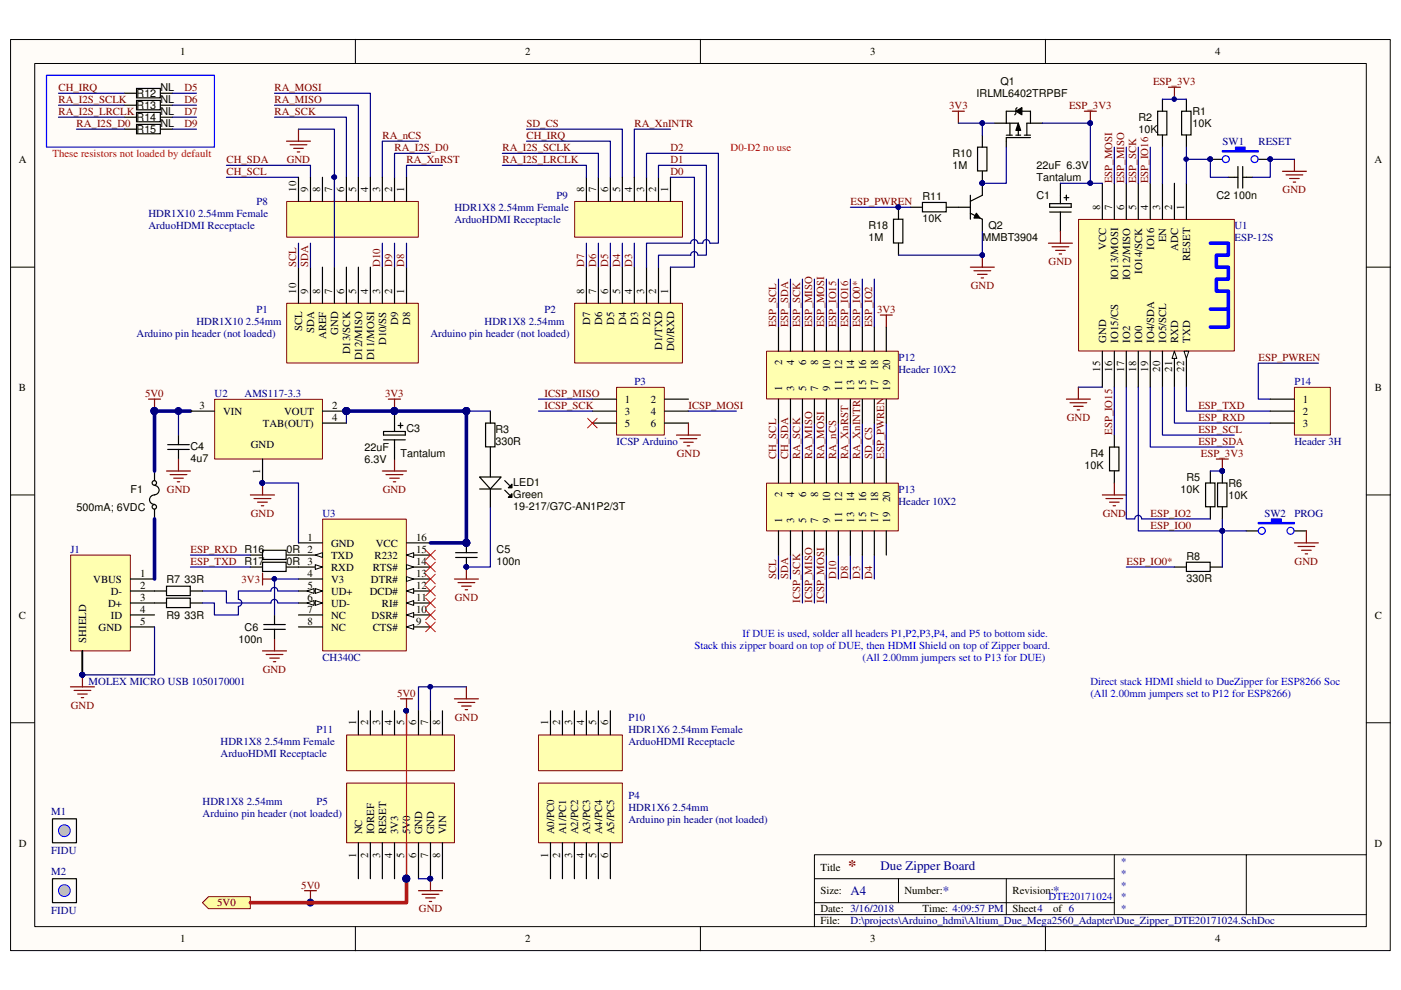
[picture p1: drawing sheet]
<svg xmlns="http://www.w3.org/2000/svg" width="297mm" height="210mm" viewBox="0 0 297 210" stroke-linecap="round" stroke-linejoin="round" font-family="sans-serif">
<defs><g id="words">
<text font-size="3.4" fill="#800000" x="179.8" y="184.6">*</text>
<g font-size="2.8" fill="#000080">
<text x="186.7" y="184.5">Due Zipper Board</text>
<text x="180.3" y="189.8">A4</text>
<text x="199.9" y="189.8">*</text>
<text x="223.3" y="189.8">*</text>
</g>
<g font-size="2.3">
<text x="38.2" y="11.7">1</text>
<text x="111.4" y="11.7">2</text>
<text x="184.5" y="11.7">3</text>
<text x="257.6" y="11.7">4</text>
<text x="29" y="20.6">R12</text>
<text x="29" y="23.1">R13</text>
<text x="34" y="21.8">NL</text>
<text x="34" y="19.3">NL</text>
<text x="207" y="20.6">IRLML6402TRPBF</text>
<text x="212.1" y="18">Q1</text>
<text x="29" y="28.2">R15</text>
<text x="29" y="25.7">R14</text>
<text x="34" y="26.9">NL</text>
<text x="34" y="24.4">NL</text>
<text x="241.4" y="25.7">R2</text>
<text x="241.4" y="28.2">10K</text>
<text x="252.8" y="26.9">10K</text>
<text x="252.8" y="24.4">R1</text>
<text x="4" y="34.5">A</text>
<text x="201.9" y="35.9">1M</text>
<text x="201.9" y="33.3">R10</text>
<text x="219.7" y="35.9">22uF 6.3V</text>
<text x="291.4" y="34.5">A</text>
<text x="62.8" y="40.6" transform="rotate(-90 62.8 40.6)">10</text>
<text x="65.4" y="40.6" transform="rotate(-90 65.4 40.6)">9</text>
<text x="67.9" y="40.6" transform="rotate(-90 67.9 40.6)">8</text>
<text x="70.4" y="40.6" transform="rotate(-90 70.4 40.6)">7</text>
<text x="73" y="40.6" transform="rotate(-90 73 40.6)">6</text>
<text x="75.5" y="40.6" transform="rotate(-90 75.5 40.6)">5</text>
<text x="78.1" y="40.6" transform="rotate(-90 78.1 40.6)">4</text>
<text x="80.6" y="40.6" transform="rotate(-90 80.6 40.6)">3</text>
<text x="83.1" y="40.6" transform="rotate(-90 83.1 40.6)">2</text>
<text x="85.7" y="40.6" transform="rotate(-90 85.7 40.6)">1</text>
<text x="123.9" y="40.6" transform="rotate(-90 123.9 40.6)">8</text>
<text x="126.4" y="40.6" transform="rotate(-90 126.4 40.6)">7</text>
<text x="128.9" y="40.6" transform="rotate(-90 128.9 40.6)">6</text>
<text x="131.5" y="40.6" transform="rotate(-90 131.5 40.6)">5</text>
<text x="134" y="40.6" transform="rotate(-90 134 40.6)">4</text>
<text x="136.6" y="40.6" transform="rotate(-90 136.6 40.6)">3</text>
<text x="139.1" y="40.6" transform="rotate(-90 139.1 40.6)">2</text>
<text x="141.6" y="40.6" transform="rotate(-90 141.6 40.6)">1</text>
<text x="219.7" y="38.4">Tantalum</text>
<text x="195.6" y="47">10K</text>
<text x="195.6" y="42.5">R11</text>
<text x="219.7" y="42.2">C1</text>
<text x="233.3" y="44.4" transform="rotate(-90 233.3 44.4)">8</text>
<text x="235.8" y="44.4" transform="rotate(-90 235.8 44.4)">7</text>
<text x="238.3" y="44.4" transform="rotate(-90 238.3 44.4)">6</text>
<text x="240.9" y="44.4" transform="rotate(-90 240.9 44.4)">5</text>
<text x="243.4" y="44.4" transform="rotate(-90 243.4 44.4)">4</text>
<text x="246" y="44.4" transform="rotate(-90 246 44.4)">3</text>
<text x="248.5" y="44.4" transform="rotate(-90 248.5 44.4)">2</text>
<text x="251.1" y="44.4" transform="rotate(-90 251.1 44.4)">1</text>
<text x="257.9" y="42.2">C2</text>
<text x="261.5" y="42.2">100n</text>
<text x="184.1" y="51.1">1M</text>
<text x="184.1" y="48.6">R18</text>
<text x="208.3" y="51.1">MMBT3904</text>
<text x="209.6" y="48.6">Q2</text>
<text x="234.5" y="53" transform="rotate(-90 234.5 53)">VCC</text>
<text x="244.7" y="53" transform="rotate(-90 244.7 53)">IO16</text>
<text x="247.2" y="51.4" transform="rotate(-90 247.2 51.4)">EN</text>
<text x="249.8" y="53.1" transform="rotate(-90 249.8 53.1)">ADC</text>
<text x="237.1" y="59.4" transform="rotate(-90 237.1 59.4)">IO13/MOSI</text>
<text x="239.6" y="59.4" transform="rotate(-90 239.6 59.4)">IO12/MISO</text>
<text x="242.1" y="58.1" transform="rotate(-90 242.1 58.1)">IO14/SCK</text>
<text x="252.3" y="55.3" transform="rotate(-90 252.3 55.3)">RESET</text>
<text x="62.8" y="62.3" transform="rotate(-90 62.8 62.3)">10</text>
<text x="65.4" y="62.3" transform="rotate(-90 65.4 62.3)">9</text>
<text x="67.9" y="62.3" transform="rotate(-90 67.9 62.3)">8</text>
<text x="70.4" y="62.3" transform="rotate(-90 70.4 62.3)">7</text>
<text x="73" y="62.3" transform="rotate(-90 73 62.3)">6</text>
<text x="75.5" y="62.3" transform="rotate(-90 75.5 62.3)">5</text>
<text x="78.1" y="62.3" transform="rotate(-90 78.1 62.3)">4</text>
<text x="80.6" y="62.3" transform="rotate(-90 80.6 62.3)">3</text>
<text x="83.1" y="62.3" transform="rotate(-90 83.1 62.3)">2</text>
<text x="85.7" y="62.3" transform="rotate(-90 85.7 62.3)">1</text>
<text x="123.9" y="62.3" transform="rotate(-90 123.9 62.3)">8</text>
<text x="126.4" y="62.3" transform="rotate(-90 126.4 62.3)">7</text>
<text x="128.9" y="62.3" transform="rotate(-90 128.9 62.3)">6</text>
<text x="131.5" y="62.3" transform="rotate(-90 131.5 62.3)">5</text>
<text x="134" y="62.3" transform="rotate(-90 134 62.3)">4</text>
<text x="136.6" y="62.3" transform="rotate(-90 136.6 62.3)">3</text>
<text x="139.1" y="62.3" transform="rotate(-90 139.1 62.3)">2</text>
<text x="141.6" y="62.3" transform="rotate(-90 141.6 62.3)">1</text>
<text x="64.1" y="70.3" transform="rotate(-90 64.1 70.3)">SCL</text>
<text x="66.6" y="70.7" transform="rotate(-90 66.6 70.7)">SDA</text>
<text x="69.2" y="71.9" transform="rotate(-90 69.2 71.9)">AREF</text>
<text x="71.7" y="71" transform="rotate(-90 71.7 71)">GND</text>
<text x="84.4" y="68.9" transform="rotate(-90 84.4 68.9)">D9</text>
<text x="86.9" y="68.9" transform="rotate(-90 86.9 68.9)">D8</text>
<text x="125.1" y="68.9" transform="rotate(-90 125.1 68.9)">D7</text>
<text x="127.7" y="68.9" transform="rotate(-90 127.7 68.9)">D6</text>
<text x="130.2" y="68.9" transform="rotate(-90 130.2 68.9)">D5</text>
<text x="132.8" y="68.9" transform="rotate(-90 132.8 68.9)">D4</text>
<text x="135.3" y="68.9" transform="rotate(-90 135.3 68.9)">D3</text>
<text x="137.8" y="68.9" transform="rotate(-90 137.8 68.9)">D2</text>
<text x="74.2" y="75.1" transform="rotate(-90 74.2 75.1)">D13/SCK</text>
<text x="76.8" y="76.4" transform="rotate(-90 76.8 76.4)">D12/MISO</text>
<text x="79.3" y="76.4" transform="rotate(-90 79.3 76.4)">D11/MOSI</text>
<text x="81.9" y="73.2" transform="rotate(-90 81.9 73.2)">D10/SS</text>
<text x="140.4" y="74.3" transform="rotate(-90 140.4 74.3)">D1/TXD</text>
<text x="142.9" y="74.4" transform="rotate(-90 142.9 74.4)">D0/RXD</text>
<text x="165.8" y="77.4" transform="rotate(-90 165.8 77.4)">2</text>
<text x="168.4" y="77.4" transform="rotate(-90 168.4 77.4)">4</text>
<text x="170.9" y="77.4" transform="rotate(-90 170.9 77.4)">6</text>
<text x="173.5" y="77.4" transform="rotate(-90 173.5 77.4)">8</text>
<text x="234.5" y="72.7" transform="rotate(-90 234.5 72.7)">GND</text>
<text x="237.1" y="72.7" transform="rotate(-90 237.1 72.7)">IO15/CS</text>
<text x="239.6" y="72.7" transform="rotate(-90 239.6 72.7)">IO2</text>
<text x="242.1" y="72.7" transform="rotate(-90 242.1 72.7)">IO0</text>
<text x="244.7" y="72.7" transform="rotate(-90 244.7 72.7)">IO4/SDA</text>
<text x="247.2" y="72.7" transform="rotate(-90 247.2 72.7)">IO5/SCL</text>
<text x="249.8" y="72.7" transform="rotate(-90 249.8 72.7)">RXD</text>
<text x="252.3" y="72.7" transform="rotate(-90 252.3 72.7)">TXD</text>
<text x="4" y="82.8">B</text>
<text x="165.8" y="82.8" transform="rotate(-90 165.8 82.8)">1</text>
<text x="168.4" y="82.8" transform="rotate(-90 168.4 82.8)">3</text>
<text x="170.9" y="82.8" transform="rotate(-90 170.9 82.8)">5</text>
<text x="173.5" y="82.8" transform="rotate(-90 173.5 82.8)">7</text>
<text x="176" y="82.8" transform="rotate(-90 176 82.8)">9</text>
<text x="176" y="78.5" transform="rotate(-90 176 78.5)">10</text>
<text x="178.6" y="82.8" transform="rotate(-90 178.6 82.8)">11</text>
<text x="178.6" y="78.5" transform="rotate(-90 178.6 78.5)">12</text>
<text x="181.1" y="82.8" transform="rotate(-90 181.1 82.8)">13</text>
<text x="181.1" y="78.5" transform="rotate(-90 181.1 78.5)">14</text>
<text x="183.6" y="82.8" transform="rotate(-90 183.6 82.8)">15</text>
<text x="183.6" y="78.5" transform="rotate(-90 183.6 78.5)">16</text>
<text x="186.2" y="82.8" transform="rotate(-90 186.2 82.8)">17</text>
<text x="186.2" y="78.5" transform="rotate(-90 186.2 78.5)">18</text>
<text x="188.7" y="82.8" transform="rotate(-90 188.7 82.8)">19</text>
<text x="188.7" y="78.5" transform="rotate(-90 188.7 78.5)">20</text>
<text x="233.3" y="78.8" transform="rotate(-90 233.3 78.8)">15</text>
<text x="235.8" y="78.8" transform="rotate(-90 235.8 78.8)">16</text>
<text x="238.3" y="78.8" transform="rotate(-90 238.3 78.8)">17</text>
<text x="240.9" y="78.8" transform="rotate(-90 240.9 78.8)">18</text>
<text x="243.4" y="78.8" transform="rotate(-90 243.4 78.8)">19</text>
<text x="246" y="78.8" transform="rotate(-90 246 78.8)">20</text>
<text x="248.5" y="78.8" transform="rotate(-90 248.5 78.8)">21</text>
<text x="251.1" y="78.8" transform="rotate(-90 251.1 78.8)">22</text>
<text x="291.5" y="82.8">B</text>
<text x="42.3" y="86.7">3</text>
<text x="47.3" y="88">VIN</text>
<text x="60.2" y="88">VOUT</text>
<text x="70.4" y="86.7">2</text>
<text x="70.4" y="89.2">4</text>
<text x="132.5" y="85.4">1</text>
<text x="132.5" y="88">3</text>
<text x="138" y="85.4">2</text>
<text x="138" y="88">4</text>
<text x="276.2" y="85.4">1</text>
<text x="276.2" y="88">2</text>
<text x="40.4" y="95.3">C4</text>
<text x="53.2" y="95.1">GND</text>
<text x="55.7" y="90.5">TAB(OUT)</text>
<text x="77.3" y="95.6">22uF</text>
<text x="86.2" y="91.5">C3</text>
<text x="105" y="91.8">R3</text>
<text x="105" y="94.3">330R</text>
<text x="132.5" y="90.5">5</text>
<text x="138" y="90.5">6</text>
<text x="276.2" y="90.5">3</text>
<text x="40.4" y="97.9">4u7</text>
<text x="55.2" y="100.5" transform="rotate(-90 55.2 100.5)">1</text>
<text x="77.3" y="98.1">6.3V</text>
<text x="84.9" y="96.9">Tantalum</text>
<text x="229.9" y="99.4">10K</text>
<text x="231.2" y="96.9">R4</text>
<text x="251.5" y="101.9">R5</text>
<text x="27.7" y="104.5">F1</text>
<text x="108.8" y="103">LED1</text>
<text x="108.8" y="105.5">Green</text>
<text x="165.8" y="105.4" transform="rotate(-90 165.8 105.4)">2</text>
<text x="168.4" y="105.4" transform="rotate(-90 168.4 105.4)">4</text>
<text x="170.9" y="105.4" transform="rotate(-90 170.9 105.4)">6</text>
<text x="173.5" y="105.4" transform="rotate(-90 173.5 105.4)">8</text>
<text x="176" y="106.5" transform="rotate(-90 176 106.5)">10</text>
<text x="178.6" y="106.5" transform="rotate(-90 178.6 106.5)">12</text>
<text x="181.1" y="106.5" transform="rotate(-90 181.1 106.5)">14</text>
<text x="183.6" y="106.5" transform="rotate(-90 183.6 106.5)">16</text>
<text x="186.2" y="106.5" transform="rotate(-90 186.2 106.5)">18</text>
<text x="188.7" y="106.5" transform="rotate(-90 188.7 106.5)">20</text>
<text x="250.3" y="104.5">10K</text>
<text x="260.5" y="105.7">10K</text>
<text x="260.5" y="103.2">R6</text>
<text x="16.3" y="108.3">500mA; 6VDC</text>
<text x="108.8" y="108">19-217/G7C-AN1P2/3T</text>
<text x="165.8" y="110.8" transform="rotate(-90 165.8 110.8)">1</text>
<text x="168.4" y="110.8" transform="rotate(-90 168.4 110.8)">3</text>
<text x="170.9" y="110.8" transform="rotate(-90 170.9 110.8)">5</text>
<text x="173.5" y="110.8" transform="rotate(-90 173.5 110.8)">7</text>
<text x="176" y="110.8" transform="rotate(-90 176 110.8)">9</text>
<text x="178.6" y="110.8" transform="rotate(-90 178.6 110.8)">11</text>
<text x="181.1" y="110.8" transform="rotate(-90 181.1 110.8)">13</text>
<text x="183.6" y="110.8" transform="rotate(-90 183.6 110.8)">15</text>
<text x="186.2" y="110.8" transform="rotate(-90 186.2 110.8)">17</text>
<text x="188.7" y="110.8" transform="rotate(-90 188.7 110.8)">19</text>
<text x="51.9" y="119.8">R17</text>
<text x="60.7" y="117.2">0R 2</text>
<text x="60.7" y="119.8">0R 3</text>
<text x="65.2" y="114.6">1</text>
<text x="70.2" y="115.9">GND</text>
<text x="70.2" y="118.4">TXD</text>
<text x="79.4" y="118.4">R232</text>
<text x="79.7" y="115.9">VCC</text>
<text x="88.2" y="117.2">15</text>
<text x="88.2" y="119.7">14</text>
<text x="88.2" y="114.6">16</text>
<text x="105.3" y="119.8">100n</text>
<text x="105.3" y="117.2">C5</text>
<text x="251.5" y="118.7">R8</text>
<text x="19.8" y="123.5">VBUS</text>
<text x="29.7" y="122.3">1</text>
<text x="29.7" y="124.8">2</text>
<text x="35.3" y="123.6">R7</text>
<text x="39.1" y="123.6">33R</text>
<text x="65.2" y="122.3">4</text>
<text x="65.2" y="124.8">5</text>
<text x="70.2" y="121">RXD</text>
<text x="70.2" y="123.5">V3</text>
<text x="78.7" y="123.5">DTR#</text>
<text x="79" y="121">RTS#</text>
<text x="88.2" y="122.3">13</text>
<text x="88.2" y="124.8">12</text>
<text x="251.5" y="123.3">330R</text>
<text x="4" y="131.2">C</text>
<text x="22.9" y="128.7">D+</text>
<text x="23.5" y="126.1">D-</text>
<text x="23.5" y="131.2">ID</text>
<text x="29.7" y="127.4">3</text>
<text x="29.7" y="129.9">4</text>
<text x="35.3" y="131.2">R9</text>
<text x="39.1" y="131.2">33R</text>
<text x="65.2" y="127.4">6</text>
<text x="65.2" y="129.9">7</text>
<text x="70.2" y="126.1">UD+</text>
<text x="70.2" y="128.7">UD-</text>
<text x="70.2" y="131.2">NC</text>
<text x="78.4" y="126.1">DCD#</text>
<text x="78.8" y="131.2">DSR#</text>
<text x="81" y="128.7">RI#</text>
<text x="88.2" y="127.4">11</text>
<text x="88.2" y="129.9">10</text>
<text x="291.5" y="131.2">C</text>
<text x="18.3" y="136.2" transform="rotate(-90 18.3 136.2)">SHIELD</text>
<text x="20.9" y="133.7">GND</text>
<text x="29.7" y="132.5">5</text>
<text x="50.6" y="136.3">100n</text>
<text x="51.9" y="133.7">C6</text>
<text x="65.2" y="132.5">8</text>
<text x="70.2" y="133.7">NC</text>
<text x="79" y="133.7">CTS#</text>
<text x="88.2" y="132.5">9</text>
<text x="75.5" y="153.8" transform="rotate(-90 75.5 153.8)">1</text>
<text x="78.1" y="153.8" transform="rotate(-90 78.1 153.8)">2</text>
<text x="80.6" y="153.8" transform="rotate(-90 80.6 153.8)">3</text>
<text x="83.1" y="153.8" transform="rotate(-90 83.1 153.8)">4</text>
<text x="85.7" y="153.8" transform="rotate(-90 85.7 153.8)">5</text>
<text x="88.2" y="153.8" transform="rotate(-90 88.2 153.8)">6</text>
<text x="90.8" y="153.8" transform="rotate(-90 90.8 153.8)">7</text>
<text x="93.3" y="153.8" transform="rotate(-90 93.3 153.8)">8</text>
<text x="116.2" y="153.8" transform="rotate(-90 116.2 153.8)">1</text>
<text x="118.8" y="153.8" transform="rotate(-90 118.8 153.8)">2</text>
<text x="121.3" y="153.8" transform="rotate(-90 121.3 153.8)">3</text>
<text x="123.9" y="153.8" transform="rotate(-90 123.9 153.8)">4</text>
<text x="126.4" y="153.8" transform="rotate(-90 126.4 153.8)">5</text>
<text x="128.9" y="153.8" transform="rotate(-90 128.9 153.8)">6</text>
<text x="4" y="179.5">D</text>
<text x="76.8" y="176.9" transform="rotate(-90 76.8 176.9)">NC</text>
<text x="79.3" y="176.9" transform="rotate(-90 79.3 176.9)">IOREF</text>
<text x="81.9" y="176.9" transform="rotate(-90 81.9 176.9)">RESET</text>
<text x="84.4" y="176.9" transform="rotate(-90 84.4 176.9)">3V3</text>
<text x="86.9" y="176.9" transform="rotate(-90 86.9 176.9)">5V0</text>
<text x="89.5" y="176.9" transform="rotate(-90 89.5 176.9)">GND</text>
<text x="92.1" y="176.9" transform="rotate(-90 92.1 176.9)">GND</text>
<text x="94.6" y="176.9" transform="rotate(-90 94.6 176.9)">VIN</text>
<text x="117.5" y="176.9" transform="rotate(-90 117.5 176.9)">A0/PC0</text>
<text x="120.1" y="176.9" transform="rotate(-90 120.1 176.9)">A1/PC1</text>
<text x="122.6" y="176.9" transform="rotate(-90 122.6 176.9)">A2/PC2</text>
<text x="125.1" y="176.9" transform="rotate(-90 125.1 176.9)">A3/PC3</text>
<text x="127.7" y="176.9" transform="rotate(-90 127.7 176.9)">A4/PC4</text>
<text x="130.2" y="176.9" transform="rotate(-90 130.2 176.9)">A5/PC5</text>
<text x="291.4" y="179.5">D</text>
<text x="75.5" y="181.9" transform="rotate(-90 75.5 181.9)">1</text>
<text x="78.1" y="181.9" transform="rotate(-90 78.1 181.9)">2</text>
<text x="80.6" y="181.9" transform="rotate(-90 80.6 181.9)">3</text>
<text x="83.1" y="181.9" transform="rotate(-90 83.1 181.9)">4</text>
<text x="85.7" y="181.9" transform="rotate(-90 85.7 181.9)">5</text>
<text x="88.2" y="181.9" transform="rotate(-90 88.2 181.9)">6</text>
<text x="90.8" y="181.9" transform="rotate(-90 90.8 181.9)">7</text>
<text x="93.3" y="181.9" transform="rotate(-90 93.3 181.9)">8</text>
<text x="116.2" y="181.9" transform="rotate(-90 116.2 181.9)">1</text>
<text x="118.8" y="181.9" transform="rotate(-90 118.8 181.9)">2</text>
<text x="121.3" y="181.9" transform="rotate(-90 121.3 181.9)">3</text>
<text x="123.9" y="181.9" transform="rotate(-90 123.9 181.9)">4</text>
<text x="126.4" y="181.9" transform="rotate(-90 126.4 181.9)">5</text>
<text x="128.9" y="181.9" transform="rotate(-90 128.9 181.9)">6</text>
<text x="173.9" y="184.6">Title</text>
<text x="173.9" y="189.7">Size:</text>
<text x="191.8" y="189.7">Number:</text>
<text x="214.7" y="189.7">Revision:</text>
<text x="173.9" y="193.5">Date: 3/16/2018</text>
<text x="173.9" y="196">File:</text>
<text x="195.6" y="193.5">Time: 4:09:57 PM</text>
<text x="214.7" y="193.5">Sheet4</text>
<text x="223.3" y="193.5">of 6</text>
<text x="38.2" y="199.8">1</text>
<text x="111.4" y="199.8">2</text>
<text x="184.5" y="199.8">3</text>
<text x="257.6" y="199.8">4</text>
</g>
<g font-size="2.3" fill="#800000">
<text x="12.4" y="21.8">RA_I2S_SCLK</text>
<text x="12.4" y="19.3">CH_IRQ</text>
<text x="39.1" y="21.8">D6</text>
<text x="39.1" y="19.3">D5</text>
<text x="58.2" y="21.8">RA_MISO</text>
<text x="58.2" y="19.3">RA_MOSI</text>
<text x="201.2" y="23.1">3V3</text>
<text x="226.6" y="23.1">ESP_3V3</text>
<text x="244.5" y="18">ESP_3V3</text>
<text x="12.4" y="24.4">RA_I2S_LRCLK</text>
<text x="16.3" y="26.9">RA_I2S_D0</text>
<text x="39.1" y="26.9">D9</text>
<text x="39.1" y="24.4">D7</text>
<text x="58.2" y="24.4">RA_SCK</text>
<text x="81.1" y="29.5">RA_nCS</text>
<text x="111.6" y="26.9">SD_CS</text>
<text x="111.6" y="29.5">CH_IRQ</text>
<text x="134.5" y="26.9">RA_XnINTR</text>
<text x="48" y="34.5">CH_SDA</text>
<text x="60.8" y="34.5">GND</text>
<text x="83.6" y="32">RA_I2S_D0</text>
<text x="86.2" y="34.5">RA_XnRST</text>
<text x="106.5" y="34.5">RA_I2S_LRCLK</text>
<text x="106.5" y="32">RA_I2S_SCLK</text>
<text x="142.2" y="34.5">D1</text>
<text x="142.2" y="32">D2</text>
<text x="48" y="37.1">CH_SCL</text>
<text x="142.2" y="37.1">D0</text>
<text x="235.8" y="38.9" transform="rotate(-90 235.8 38.9)">ESP_MOSI</text>
<text x="238.3" y="38.9" transform="rotate(-90 238.3 38.9)">ESP_MISO</text>
<text x="240.9" y="38.9" transform="rotate(-90 240.9 38.9)">ESP_SCK</text>
<text x="243.4" y="38.9" transform="rotate(-90 243.4 38.9)">ESP_IO16</text>
<text x="271.9" y="40.9">GND</text>
<text x="180.3" y="43.5">ESP_PWREN</text>
<text x="62.8" y="56.7" transform="rotate(-90 62.8 56.7)">SCL</text>
<text x="65.4" y="56.7" transform="rotate(-90 65.4 56.7)">SDA</text>
<text x="80.6" y="56.7" transform="rotate(-90 80.6 56.7)">D10</text>
<text x="83.1" y="56.7" transform="rotate(-90 83.1 56.7)">D9</text>
<text x="85.7" y="56.7" transform="rotate(-90 85.7 56.7)">D8</text>
<text x="123.9" y="56.7" transform="rotate(-90 123.9 56.7)">D7</text>
<text x="126.4" y="56.7" transform="rotate(-90 126.4 56.7)">D6</text>
<text x="128.9" y="56.7" transform="rotate(-90 128.9 56.7)">D5</text>
<text x="131.5" y="56.7" transform="rotate(-90 131.5 56.7)">D4</text>
<text x="134" y="56.7" transform="rotate(-90 134 56.7)">D3</text>
<text x="222.3" y="56.2">GND</text>
<text x="205.8" y="61.3">GND</text>
<text x="164.5" y="69.4" transform="rotate(-90 164.5 69.4)">ESP_SCL</text>
<text x="167.1" y="69.4" transform="rotate(-90 167.1 69.4)">ESP_SDA</text>
<text x="169.6" y="69.4" transform="rotate(-90 169.6 69.4)">ESP_SCK</text>
<text x="172.2" y="69.4" transform="rotate(-90 172.2 69.4)">ESP_MISO</text>
<text x="174.7" y="69.4" transform="rotate(-90 174.7 69.4)">ESP_MOSI</text>
<text x="177.3" y="69.4" transform="rotate(-90 177.3 69.4)">ESP_IO15</text>
<text x="179.8" y="69.4" transform="rotate(-90 179.8 69.4)">ESP_IO16</text>
<text x="182.4" y="69.4" transform="rotate(-90 182.4 69.4)">ESP_IO0*</text>
<text x="184.9" y="69.4" transform="rotate(-90 184.9 69.4)">ESP_IO2</text>
<text x="186" y="66.3">3V3</text>
<text x="266.8" y="76.5">ESP_PWREN</text>
<text x="30.8" y="84.1">5V0</text>
<text x="81.7" y="84.1">3V3</text>
<text x="115.4" y="86.7">ICSP_SCK</text>
<text x="115.4" y="84.1">ICSP_MISO</text>
<text x="146" y="86.7">ICSP_MOSI</text>
<text x="226.2" y="89.2">GND</text>
<text x="254.1" y="86.7">ESP_TXD</text>
<text x="254.1" y="89.2">ESP_RXD</text>
<text x="235.8" y="92.2" transform="rotate(-90 235.8 92.2)">ESP_IO15</text>
<text x="254.1" y="94.3">ESP_SDA</text>
<text x="254.1" y="91.8">ESP_SCL</text>
<text x="143.5" y="96.9">GND</text>
<text x="164.5" y="97.4" transform="rotate(-90 164.5 97.4)">CH_SCL</text>
<text x="167.1" y="97.4" transform="rotate(-90 167.1 97.4)">CH_SDA</text>
<text x="169.6" y="97.4" transform="rotate(-90 169.6 97.4)">RA_SCK</text>
<text x="172.2" y="97.4" transform="rotate(-90 172.2 97.4)">RA_MISO</text>
<text x="174.7" y="97.4" transform="rotate(-90 174.7 97.4)">RA_MOSI</text>
<text x="177.3" y="97.4" transform="rotate(-90 177.3 97.4)">RA_nCS</text>
<text x="179.8" y="97.4" transform="rotate(-90 179.8 97.4)">RA_XnRST</text>
<text x="182.4" y="97.4" transform="rotate(-90 182.4 97.4)">RA_XnINTR</text>
<text x="184.9" y="97.4" transform="rotate(-90 184.9 97.4)">SD_CS</text>
<text x="187.4" y="97.4" transform="rotate(-90 187.4 97.4)">ESP_PWREN</text>
<text x="254.6" y="96.9">ESP_3V3</text>
<text x="35.4" y="104.5">GND</text>
<text x="81.1" y="104.5">GND</text>
<text x="53.2" y="109.6">GND</text>
<text x="233.8" y="109.6">GND</text>
<text x="243.9" y="112.1">ESP_IO0</text>
<text x="243.9" y="109.6">ESP_IO2</text>
<text x="40.4" y="117.2">ESP_RXD R16</text>
<text x="40.4" y="119.7">ESP_TXD</text>
<text x="238.8" y="119.7">ESP_IO0*</text>
<text x="274.5" y="119.7">GND</text>
<text x="51.2" y="123.5">3V3</text>
<text x="164.5" y="122.8" transform="rotate(-90 164.5 122.8)">SCL</text>
<text x="167.1" y="122.8" transform="rotate(-90 167.1 122.8)">SDA</text>
<text x="177.3" y="122.8" transform="rotate(-90 177.3 122.8)">D10</text>
<text x="179.8" y="122.8" transform="rotate(-90 179.8 122.8)">D8</text>
<text x="182.4" y="122.8" transform="rotate(-90 182.4 122.8)">D3</text>
<text x="184.9" y="122.8" transform="rotate(-90 184.9 122.8)">D4</text>
<text x="96.4" y="127.4">GND</text>
<text x="169.6" y="127.8" transform="rotate(-90 169.6 127.8)">ICSP_SCK</text>
<text x="172.2" y="127.8" transform="rotate(-90 172.2 127.8)">ICSP_MISO</text>
<text x="174.7" y="127.8" transform="rotate(-90 174.7 127.8)">ICSP_MOSI</text>
<text x="55.7" y="142.6">GND</text>
<text x="84.2" y="147.7">5V0</text>
<text x="15" y="150.2">GND</text>
<text x="96.4" y="152.8">GND</text>
<text x="63.9" y="188.4">5V0</text>
<text x="46.1" y="192.2">5V0</text>
<text x="88.8" y="193.5">GND</text>
</g>
<g font-size="2.3" fill="#f00">
<text x="11.1" y="33.3">These resistors not loaded by default</text>
<text x="154.9" y="32">D0-D2 no use</text>
</g>
<g font-size="2.3" fill="#000080">
<text x="259.2" y="30.7">SW1</text>
<text x="266.8" y="30.7">RESET</text>
<text x="31.5" y="46">HDR1X10 2.54mm Female</text>
<text x="54.4" y="43.5">P8</text>
<text x="96.3" y="47.3">ArduoHDMI Receptacle</text>
<text x="96.3" y="44.7">HDR1X8 2.54mm Female</text>
<text x="118" y="42.2">P9</text>
<text x="31.5" y="48.6">ArduoHDMI Receptacle</text>
<text x="261.7" y="48.6">U1</text>
<text x="261.7" y="51.1">ESP-12S</text>
<text x="29" y="71.4">Arduino pin header (not loaded)</text>
<text x="41.7" y="68.9">HDR1X10 2.54mm</text>
<text x="54.4" y="66.3">P1</text>
<text x="91.3" y="71.4">Arduino pin header (not loaded)</text>
<text x="102.7" y="68.9">HDR1X8 2.54mm</text>
<text x="115.4" y="66.3">P2</text>
<text x="190.5" y="76.5">P12</text>
<text x="134.5" y="81.6">P3</text>
<text x="190.5" y="79">Header 10X2</text>
<text x="274.4" y="81.6">P14</text>
<text x="45.5" y="84.1">U2</text>
<text x="51.9" y="84.1">AMS117-3.3</text>
<text x="130.7" y="94.3">ICSP Arduino</text>
<text x="274.4" y="94.3">Header 3H</text>
<text x="190.5" y="104.5">P13</text>
<text x="190.5" y="107">Header 10X2</text>
<text x="68.4" y="109.6">U3</text>
<text x="268.1" y="109.6">SW2</text>
<text x="274.4" y="109.6">PROG</text>
<text x="14.9" y="117.2">J1</text>
<text x="68.4" y="140.1">CH340C</text>
<text x="18.8" y="145.2">MOLEX MICRO USB 1050170001</text>
<text x="67.1" y="155.3">P11</text>
<text x="133.3" y="152.8">P10</text>
<text x="133.3" y="155.3">HDR1X6 2.54mm Female</text>
<text x="46.8" y="160.4">ArduoHDMI Receptacle</text>
<text x="46.8" y="157.9">HDR1X8 2.54mm Female</text>
<text x="133.3" y="157.9">ArduoHDMI Receptacle</text>
<text x="10.9" y="172.9">M1</text>
<text x="43" y="170.6">HDR1X8 2.54mm</text>
<text x="43" y="173.1">Arduino pin header (not loaded)</text>
<text x="67.1" y="170.6">P5</text>
<text x="133.3" y="169.3">P4</text>
<text x="133.3" y="171.9">HDR1X6 2.54mm</text>
<text x="133.3" y="174.4">Arduino pin header (not loaded)</text>
<text x="10.9" y="181">FIDU</text>
<text x="10.9" y="185.6">M2</text>
<text x="237.6" y="183.3">*</text>
<text x="237.6" y="185.8">*</text>
<text x="237.6" y="188.4">*</text>
<text x="237.6" y="190.9">*</text>
<text x="10.9" y="193.7">FIDU</text>
<text x="180.3" y="196">D:\projects\Arduino_hdmi\Altium_Due_Mega2560_Adapter\Due_Zipper_DTE20171024.SchDoc</text>
<text x="237.6" y="193.5">*</text>
</g>
<g font-size="2.3" fill="#00f">
<text x="147.2" y="137.5">Stack this zipper board on top of DUE, then HDMI Shield on top of Zipper board.</text>
<text x="157.4" y="135">If DUE is used, solder all headers P1,P2,P3,P4, and P5 to bottom side.</text>
<text x="182.9" y="140.1">(All 2.00mm jumpers set to P13 for DUE)</text>
<text x="231.2" y="145.2">Direct stack HDMI shield to DueZipper for ESP8266 Soc</text>
<text x="231.2" y="147.7">(All 2.00mm jumpers set to P12 for ESP8266)</text>
<text x="222.3" y="190.9">DTE20171024</text>
</g>
</g></defs>
<path d="M2.3 8.4h292.5v193.1h-292.5z" fill="#fffcf8"/>
<path d="M2.2 8.4h292.6v193.1h-292.6z" fill="none" stroke="#000" stroke-width=".21"/>
<path d="M7.4 13.5h282.3v183h-282.3z" fill="#fffcf8"/>
<g fill="none" stroke="#000" stroke-width=".21">
<path d="M7.4 13.5h282.3v183h-282.3zM75.3 8.3v5.1M148.5 8.3v5.1M221.7 8.3v5.1M2.2 56.6h5.1M289.7 56.6h5.1M2.2 104.9h5.1M289.7 104.9h5.1M2.2 153.2h5.1M289.7 153.2h5.1M75.3 196.5v5.1M148.5 196.5v5.1"/>
<path d="M172.7 186.3h63.6M172.7 193.9h117M172.7 191.4h63.6M190.5 186.3v5.1M213.4 186.3v7.6M221.7 196.5v5.1M236.3 181.2v12.7M264.2 181.2h-91.5v15.3M289.7 181.2h-25.5v12.7"/>
</g>
<path d="M64.6 188.8h2.5M65.8 188.8v2.6" fill="none" stroke="#800000" stroke-width=".25"/>
<circle cx="65.8" cy="191.4" r=".74" fill="#000080"/>
<circle cx="65.8" cy="191.4" r=".74" fill="none" stroke="#000080" stroke-width=".21"/>
<path d="M130.8 82.2h10v10h-10z" fill="#ffffb0"/>
<path d="M130.7 82.1h10.1v10.1h-10.1z" fill="none" stroke="#800000" stroke-width=".21"/>
<path d="M125.6 84.6h5.1M125.6 87.2h5.1M125.6 89.7h5.1M140.9 84.6h5.1M140.9 87.2h5.1M140.9 89.7h5.1" fill="none" stroke="#000" stroke-width=".25"/>
<path d="M143.4 92.2h5.1M144.2 93h3.5M144.9 93.8h2.1M145.7 94.5h.5M146 89.7v2.5" fill="none" stroke="#800000" stroke-width=".25"/>
<path d="M42.9 191.4l1.3-1.3h8.9v2.6h-8.9z" fill-rule="evenodd" fill="#ffff80"/>
<path d="M42.9 191.4l1.3-1.3h8.9v2.6h-8.9z" fill="none" stroke="#800000" stroke-width=".21"/>
<path d="M124.6 88.7l2 2M126.6 88.7l-2 2" fill="none" stroke="#f00" stroke-width=".21"/>
<path d="M114.2 87.2h11.4" fill="none" stroke="#000080" stroke-width=".25"/>
<path d="M84.9 148.2h2.6M86.2 148.2v2.5" fill="none" stroke="#800000" stroke-width=".25"/>
<circle cx="86.1" cy="150.7" r=".49" fill="#000080"/>
<circle cx="86.1" cy="150.7" r=".49" fill="none" stroke="#000080" stroke-width=".21"/>
<path d="M96.3 148.2h5.1M97.1 148.9h3.6M97.9 149.7h2M98.6 150.5h.5M98.9 145.6v2.6" fill="none" stroke="#800000" stroke-width=".25"/>
<path d="M91.3 145.6v5.1" fill="none" stroke="#000080" stroke-width=".25"/>
<circle cx="91.2" cy="145.6" r=".5" fill="#000080"/>
<circle cx="91.2" cy="145.6" r=".5" fill="none" stroke="#000080" stroke-width=".21"/>
<path d="M58.2 19.8h20.3v17.8M58.2 22.3h17.8v15.3M98.9 145.6h-10.2v5.1" fill="none" stroke="#000080" stroke-width=".25"/>
<path d="M60.7 29.9h5.1M61.5 30.7h3.6M62.3 31.5h2M63 32.2h.5M63.3 27.4v2.5" fill="none" stroke="#800000" stroke-width=".25"/>
<circle cx="13.6" cy="176.1" r="1.25" fill="#c0c0c0"/>
<circle cx="13.6" cy="176.1" r="1.25" fill="none" stroke="#00f" stroke-width=".21"/>
<path d="M11.1 173.6h5.1v5.1h-5.1z" fill="none" stroke="#000" stroke-width=".25"/>
<circle cx="13.6" cy="188.8" r="1.25" fill="#c0c0c0"/>
<circle cx="13.6" cy="188.8" r="1.25" fill="none" stroke="#00f" stroke-width=".21"/>
<path d="M245.4 23.6h2v5h-2zM246.5 21v2.6M246.5 28.7v2.5M256.6 33.8h2.6M256.6 99.9v2.5M255.6 102.4h2v5h-2zM256.6 107.5v2.5M11.1 186.3h5.1v5.1h-5.1z" fill="none" stroke="#000" stroke-width=".25"/>
<path d="M114.2 84.6h11.4" fill="none" stroke="#000080" stroke-width=".25"/>
<circle cx="256.6" cy="33.7" r=".48" fill="#000080"/>
<circle cx="256.6" cy="33.7" r=".48" fill="none" stroke="#000080" stroke-width=".21"/>
<path d="M266.8 33.8h2.5" fill="none" stroke="#000" stroke-width=".25"/>
<circle cx="269.3" cy="33.7" r=".48" fill="#000080"/>
<circle cx="269.3" cy="33.7" r=".48" fill="none" stroke="#000080" stroke-width=".21"/>
<path d="M259.2 32h2.8v-.8h2v.8h2.8v.2h-7.6z" fill-rule="evenodd" fill="#00f"/>
<g fill="none" stroke="#00f" stroke-width=".25">
<path d="M259.2 32h2.8v-.8h2v.8h2.8v.2h-7.6z"/>
<circle cx="259.9" cy="33.7" r=".74"/>
<circle cx="266" cy="33.7" r=".73"/>
</g>
<circle cx="256.6" cy="33.7" r=".48" fill="#000080"/>
<circle cx="256.6" cy="33.7" r=".48" fill="none" stroke="#000080" stroke-width=".21"/>
<circle cx="269.3" cy="33.7" r=".48" fill="#000080"/>
<circle cx="269.3" cy="33.7" r=".48" fill="none" stroke="#000080" stroke-width=".21"/>
<path d="M228.7 46.6h33v27.8h-33z" fill="#ffffb0"/>
<path d="M228.7 46.5h33v27.9h-33z" fill="none" stroke="#800000" stroke-width=".21"/>
<g fill="none" stroke="#000" stroke-width=".25">
<path d="M233.7 38.9v7.6M236.3 38.9v7.6M238.8 38.9v7.6M241.3 38.9v7.6M243.9 38.9v7.6M246.5 38.9v7.6M249 38.9v7.6M251.5 38.9v7.6M233.7 74.5v7.6M236.3 74.5v7.6M238.8 74.5v7.6M241.3 74.5v7.6"/>
<path d="M243.9 74.5v7.6M246.5 74.5v7.6M249 74.5v7.6"/>
</g>
<path d="M249 74.5l.5 1.5h-1z" fill="#fffcf8"/>
<path d="M249 74.5l.5 1.5h-1z" fill="none" stroke="#000" stroke-width=".21"/>
<path d="M251.5 74.5v7.6" fill="none" stroke="#000" stroke-width=".25"/>
<path d="M251 74.5h1l-.5 1.5z" fill="#fffcf8"/>
<path d="M251 74.5h1l-.5 1.5z" fill="none" stroke="#000" stroke-width=".21"/>
<path d="M256.6 51.6h3.8v2.5h-2.5v2.5h2.5v2.6h-2.5v2.5h2.5v7.6h-3.8M256.6 65.5h3.8" fill="none" stroke="#00f" stroke-width=".76"/>
<path d="M264.2 112.6h2.6M274.4 112.6h2.6" fill="none" stroke="#000" stroke-width=".25"/>
<path d="M266.8 110.8h2.8v-.8h2v.8h2.8v.2h-7.6z" fill-rule="evenodd" fill="#00f"/>
<g fill="none" stroke="#00f" stroke-width=".25">
<path d="M266.8 110.8h2.8v-.8h2v.8h2.8v.2h-7.6z"/>
<circle cx="267.5" cy="112.5" r=".74"/>
<circle cx="273.6" cy="112.5" r=".74"/>
</g>
<path d="M250.5 23.6h2v5h-2zM251.5 21v2.6M251.5 28.7v2.5M235.2 94.8h2v5h-2zM236.3 92.2v2.6M236.3 99.9v2.5M259.2 99.9v2.5" fill="none" stroke="#000" stroke-width=".25"/>
<circle cx="259.1" cy="99.8" r=".49" fill="#000080"/>
<circle cx="259.1" cy="99.8" r=".49" fill="none" stroke="#000080" stroke-width=".21"/>
<path d="M258.1 102.4h2v5h-2zM259.2 107.5v2.5" fill="none" stroke="#000" stroke-width=".25"/>
<circle cx="259.1" cy="99.8" r=".49" fill="#000080"/>
<circle cx="259.1" cy="99.8" r=".49" fill="none" stroke="#000080" stroke-width=".21"/>
<path d="M82.3 84.6h2.6M83.6 84.6v2.6" fill="none" stroke="#800000" stroke-width=".25"/>
<circle cx="83.6" cy="87.1" r=".73" fill="#000080"/>
<circle cx="83.6" cy="87.1" r=".73" fill="none" stroke="#000080" stroke-width=".21"/>
<path d="M15 117.7h12.6v20.3h-12.6z" fill="#ffffb0"/>
<path d="M15 117.7h12.6v20.3h-12.6z" fill="none" stroke="#800000" stroke-width=".21"/>
<path d="M17.5 138v5.1M27.6 122.8h5.2M27.6 125.3h5.2M27.6 127.8h5.2M27.6 130.4h5.2M27.6 132.9h5.2" fill="none" stroke="#000" stroke-width=".25"/>
<circle cx="17.5" cy="143.1" r=".49" fill="#000080"/>
<circle cx="17.5" cy="143.1" r=".49" fill="none" stroke="#000080" stroke-width=".21"/>
<path d="M17.5 138v5.1" fill="none" stroke="#000" stroke-width=".25"/>
<circle cx="17.5" cy="143.1" r=".49" fill="#000080"/>
<circle cx="17.5" cy="143.1" r=".49" fill="none" stroke="#000080" stroke-width=".21"/>
<path d="M17.5 138v5.1" fill="none" stroke="#000" stroke-width=".25"/>
<circle cx="17.5" cy="143.1" r=".49" fill="#000080"/>
<circle cx="17.5" cy="143.1" r=".49" fill="none" stroke="#000080" stroke-width=".21"/>
<path d="M17.5 138v5.1" fill="none" stroke="#000" stroke-width=".25"/>
<circle cx="17.5" cy="143.1" r=".49" fill="#000080"/>
<circle cx="17.5" cy="143.1" r=".49" fill="none" stroke="#000080" stroke-width=".21"/>
<path d="M17.5 138v5.1" fill="none" stroke="#000" stroke-width=".25"/>
<circle cx="17.5" cy="143.1" r=".49" fill="#000080"/>
<circle cx="17.5" cy="143.1" r=".49" fill="none" stroke="#000080" stroke-width=".21"/>
<path d="M17.5 138v5.1" fill="none" stroke="#000" stroke-width=".25"/>
<circle cx="17.5" cy="143.1" r=".49" fill="#000080"/>
<circle cx="17.5" cy="143.1" r=".49" fill="none" stroke="#000080" stroke-width=".21"/>
<circle cx="17.5" cy="143.1" r=".49" fill="#000080"/>
<circle cx="17.5" cy="143.1" r=".49" fill="none" stroke="#000080" stroke-width=".21"/>
<circle cx="17.5" cy="143.1" r=".49" fill="#000080"/>
<circle cx="17.5" cy="143.1" r=".49" fill="none" stroke="#000080" stroke-width=".21"/>
<circle cx="17.5" cy="143.1" r=".49" fill="#000080"/>
<circle cx="17.5" cy="143.1" r=".49" fill="none" stroke="#000080" stroke-width=".21"/>
<circle cx="17.5" cy="143.1" r=".49" fill="#000080"/>
<circle cx="17.5" cy="143.1" r=".49" fill="none" stroke="#000080" stroke-width=".21"/>
<circle cx="17.5" cy="143.1" r=".49" fill="#000080"/>
<circle cx="17.5" cy="143.1" r=".49" fill="none" stroke="#000080" stroke-width=".21"/>
<circle cx="17.5" cy="143.1" r=".49" fill="#000080"/>
<circle cx="17.5" cy="143.1" r=".49" fill="none" stroke="#000080" stroke-width=".21"/>
<path d="M53.1 104.9h5.1M53.8 105.7h3.6M54.6 106.5h2.1M55.4 107.2h.5M55.7 102.4v2.5" fill="none" stroke="#800000" stroke-width=".25"/>
<circle cx="55.6" cy="102.4" r=".49" fill="#000080"/>
<circle cx="55.6" cy="102.4" r=".49" fill="none" stroke="#000080" stroke-width=".21"/>
<path d="M14.9 145.6h5.1M15.7 146.4h3.6M16.5 147.2h2M17.2 147.9h.5M17.5 143.1v2.5" fill="none" stroke="#800000" stroke-width=".25"/>
<circle cx="17.5" cy="143.1" r=".49" fill="#000080"/>
<circle cx="17.5" cy="143.1" r=".49" fill="none" stroke="#000080" stroke-width=".21"/>
<path d="M32.8 132.9v10.2h-15.3" fill="none" stroke="#000080" stroke-width=".25"/>
<circle cx="17.5" cy="143.1" r=".49" fill="#000080"/>
<circle cx="17.5" cy="143.1" r=".49" fill="none" stroke="#000080" stroke-width=".21"/>
<path d="M73.4 87.2v2.5" fill="none" stroke="#000080" stroke-width=".25"/>
<circle cx="73.4" cy="87.1" r=".74" fill="#000080"/>
<circle cx="73.4" cy="87.1" r=".74" fill="none" stroke="#000080" stroke-width=".21"/>
<path d="M81.1 99.9h5.1M83.6 97.3v2.6M81.8 100.6h3.6M82.6 101.4h2.1M83.4 102.2h.5" fill="none" stroke="#800000" stroke-width=".25"/>
<path d="M83.6 87.2v2.5" fill="none" stroke="#000" stroke-width=".25"/>
<circle cx="83.6" cy="87.1" r=".73" fill="#000080"/>
<circle cx="83.6" cy="87.1" r=".73" fill="none" stroke="#000080" stroke-width=".21"/>
<path d="M81.3 91.5h4.6v.7h-4.6zM81.3 93.3h4.6M83.6 89.7v1.8M83.6 93.3v4M84.4 90.2h1M84.9 89.7v1" fill="none" stroke="#000" stroke-width=".25"/>
<circle cx="83.6" cy="87.1" r=".73" fill="#000080"/>
<circle cx="83.6" cy="87.1" r=".73" fill="none" stroke="#000080" stroke-width=".21"/>
<path d="M35.6 95.3h4.5M35.6 94.3h4.5M37.8 92.2v2.1M37.8 95.3v2" fill="none" stroke="#000" stroke-width=".25"/>
<path d="M35.3 99.9h5.1M37.8 97.3v2.6M36.1 100.6h3.5M36.8 101.4h2.1M37.6 102.2h.5" fill="none" stroke="#800000" stroke-width=".25"/>
<path d="M37.8 87.2v5" fill="none" stroke="#000080" stroke-width=".25"/>
<circle cx="37.8" cy="87.1" r=".74" fill="#000080"/>
<circle cx="37.8" cy="87.1" r=".74" fill="none" stroke="#000080" stroke-width=".21"/>
<path d="M31.5 84.6h2.5M32.8 84.6v2.6" fill="none" stroke="#800000" stroke-width=".25"/>
<circle cx="32.7" cy="87.1" r=".73" fill="#000080"/>
<circle cx="32.7" cy="87.1" r=".73" fill="none" stroke="#000080" stroke-width=".21"/>
<path d="M224.8 38.9v4.3M222.5 43.2h4.6v.7h-4.6zM222.5 45h4.6M224.8 45v4M225.6 41.9h1M226.1 41.4v1" fill="none" stroke="#000" stroke-width=".25"/>
<path d="M55.7 138h5M56.4 138.8h3.6M57.2 139.5h2M58.2 135.5v2.5M96.3 122.8h5.1M97.1 123.5h3.6M97.9 124.3h2M98.6 125.1h.5M98.9 120.2v2.6M58 140.3h.5" fill="none" stroke="#800000" stroke-width=".25"/>
<circle cx="98.9" cy="120.2" r=".48" fill="#000080"/>
<circle cx="98.9" cy="120.2" r=".48" fill="none" stroke="#000080" stroke-width=".21"/>
<path d="M98.9 115.1v1.3" fill="none" stroke="#000" stroke-width=".25"/>
<circle cx="98.9" cy="115.1" r=".74" fill="#000080"/>
<circle cx="98.9" cy="115.1" r=".74" fill="none" stroke="#000080" stroke-width=".21"/>
<path d="M98.9 119v1.2" fill="none" stroke="#000" stroke-width=".25"/>
<circle cx="98.9" cy="120.2" r=".48" fill="#000080"/>
<circle cx="98.9" cy="120.2" r=".48" fill="none" stroke="#000080" stroke-width=".21"/>
<path d="M96.6 118.2h4.6M96.6 117.2h4.6M98.9 116.4v.8M98.9 118.2v.8" fill="none" stroke="#000" stroke-width=".25"/>
<circle cx="98.9" cy="115.1" r=".74" fill="#000080"/>
<circle cx="98.9" cy="115.1" r=".74" fill="none" stroke="#000080" stroke-width=".21"/>
<circle cx="98.9" cy="120.2" r=".48" fill="#000080"/>
<circle cx="98.9" cy="120.2" r=".48" fill="none" stroke="#000080" stroke-width=".21"/>
<path d="M68.4 110.1h17.7v27.9h-17.7z" fill="#ffffb0"/>
<path d="M68.4 110.1h17.7v27.9h-17.7z" fill="none" stroke="#800000" stroke-width=".21"/>
<path d="M63.3 115.1h5.1M63.3 117.7h5.1" fill="none" stroke="#000" stroke-width=".25"/>
<path d="M66.8 117.7l1.6-.5v1z" fill="#fffcf8"/>
<path d="M66.8 117.7l1.6-.5v1z" fill="none" stroke="#000" stroke-width=".21"/>
<path d="M63.3 120.2h5.1" fill="none" stroke="#000" stroke-width=".25"/>
<path d="M66.8 119.7l1.6 .5-1.6 .5z" fill="#fffcf8"/>
<path d="M66.8 119.7l1.6 .5-1.6 .5z" fill="none" stroke="#000" stroke-width=".21"/>
<path d="M63.3 122.8h5.1M63.3 125.3h5.1" fill="none" stroke="#000" stroke-width=".25"/>
<path d="M66.8 124.8l1.6 .5-1.6 .5z" fill="#fffcf8"/>
<path d="M66.8 124.8l1.6 .5-1.6 .5z" fill="none" stroke="#000" stroke-width=".21"/>
<path d="M65.1 125.3l1.5-.5v1z" fill="#fffcf8"/>
<path d="M65.1 125.3l1.5-.5v1z" fill="none" stroke="#000" stroke-width=".21"/>
<path d="M63.3 127.8h5.1" fill="none" stroke="#000" stroke-width=".25"/>
<path d="M66.8 127.3l1.6 .5-1.6 .6z" fill="#fffcf8"/>
<path d="M66.8 127.3l1.6 .5-1.6 .6z" fill="none" stroke="#000" stroke-width=".21"/>
<path d="M65.1 127.8l1.5-.5v1.1z" fill="#fffcf8"/>
<path d="M65.1 127.8l1.5-.5v1.1z" fill="none" stroke="#000" stroke-width=".21"/>
<path d="M63.3 130.4h5.1M63.3 132.9h5.1M86.2 132.9h5.1" fill="none" stroke="#000" stroke-width=".25"/>
<path d="M86.2 132.9l1.5-.5v1z" fill="#fffcf8"/>
<path d="M86.2 132.9l1.5-.5v1z" fill="none" stroke="#000" stroke-width=".21"/>
<path d="M86.2 130.4h5.1" fill="none" stroke="#000" stroke-width=".25"/>
<path d="M86.2 130.4l1.5-.5v1z" fill="#fffcf8"/>
<path d="M86.2 130.4l1.5-.5v1z" fill="none" stroke="#000" stroke-width=".21"/>
<path d="M86.2 127.8h5.1" fill="none" stroke="#000" stroke-width=".25"/>
<path d="M86.2 127.8l1.5-.5v1.1z" fill="#fffcf8"/>
<path d="M86.2 127.8l1.5-.5v1.1z" fill="none" stroke="#000" stroke-width=".21"/>
<path d="M86.2 125.3h5.1" fill="none" stroke="#000" stroke-width=".25"/>
<path d="M86.2 125.3l1.5-.5v1z" fill="#fffcf8"/>
<path d="M86.2 125.3l1.5-.5v1z" fill="none" stroke="#000" stroke-width=".21"/>
<path d="M86.2 122.8h5.1" fill="none" stroke="#000" stroke-width=".25"/>
<path d="M86.2 122.3l1.5 .5-1.5 .5z" fill="#fffcf8"/>
<path d="M86.2 122.3l1.5 .5-1.5 .5z" fill="none" stroke="#000" stroke-width=".21"/>
<path d="M86.2 120.2h5.1" fill="none" stroke="#000" stroke-width=".25"/>
<path d="M86.2 119.7l1.5 .5-1.5 .5z" fill="#fffcf8"/>
<path d="M86.2 119.7l1.5 .5-1.5 .5z" fill="none" stroke="#000" stroke-width=".21"/>
<path d="M86.2 117.7h5.1" fill="none" stroke="#000" stroke-width=".25"/>
<path d="M86.2 117.7l1.5-.5v1z" fill="#fffcf8"/>
<path d="M86.2 117.7l1.5-.5v1z" fill="none" stroke="#000" stroke-width=".21"/>
<path d="M86.2 115.1h5.1M55.9 133.4h4.6M55.9 132.4h4.6M58.2 130.4v2M58.2 133.4v2.1" fill="none" stroke="#000" stroke-width=".25"/>
<path d="M55.7 121.5v2.5M55.7 122.8h2.5" fill="none" stroke="#800000" stroke-width=".25"/>
<circle cx="58.2" cy="122.7" r=".46" fill="#000080"/>
<circle cx="58.2" cy="122.7" r=".46" fill="none" stroke="#000080" stroke-width=".21"/>
<path d="M63.3 122.8h-5.1v7.6" fill="none" stroke="#000080" stroke-width=".25"/>
<circle cx="58.2" cy="122.7" r=".46" fill="#000080"/>
<circle cx="58.2" cy="122.7" r=".46" fill="none" stroke="#000080" stroke-width=".21"/>
<path d="M55.7 102.4h7.6v12.7M42.9 125.3h5.1v2.5h9.4a.72 .72 0 0 1 .8-.7 .72 .72 0 0 1 .7 .7M59 127.8h4.3" fill="none" stroke="#000080" stroke-width=".25"/>
<circle cx="55.6" cy="102.4" r=".49" fill="#000080"/>
<circle cx="55.6" cy="102.4" r=".49" fill="none" stroke="#000080" stroke-width=".21"/>
<g fill="none" stroke="#f00" stroke-width=".21">
<path d="M90.3 116.7l2 2M90.3 119.2l2 2M92.3 116.7l-2 2M92.3 119.2l-2 2M90.3 121.8l2 2M90.3 124.3l2 2M90.3 126.8l2 2.1M90.3 129.4l2 2M90.3 131.9l2 2M92.3 121.8l-2 2M92.3 124.3l-2 2M92.3 126.8l-2 2.1"/>
<path d="M92.3 129.4l-2 2M92.3 131.9l-2 2"/>
</g>
<path d="M32.8 127.8h2.5M32.8 125.3h2.5M35.3 126.8h5v2h-5zM35.3 124.3h5v2h-5zM40.4 127.8h2.5M40.4 125.3h2.5" fill="none" stroke="#000" stroke-width=".25"/>
<path d="M104 107.5v12.7h-5.1" fill="none" stroke="#000080" stroke-width=".25"/>
<circle cx="98.9" cy="120.2" r=".48" fill="#000080"/>
<circle cx="98.9" cy="120.2" r=".48" fill="none" stroke="#000080" stroke-width=".21"/>
<path d="M103 89.7h1.9v5h-1.9zM104 87.2v2.5M104 94.8v2.5M251.5 119.2h5.1v2h-5.1zM249 120.2h2.5M256.6 120.2h2.6" fill="none" stroke="#000" stroke-width=".25"/>
<path d="M58.2 24.8h15.2v12.8M98.9 87.2h5.1" fill="none" stroke="#000080" stroke-width=".25"/>
<circle cx="98.9" cy="87.1" r=".74" fill="#000080"/>
<circle cx="98.9" cy="87.1" r=".74" fill="none" stroke="#000080" stroke-width=".21"/>
<path d="M60.8 64.3h27.9v12.7h-27.9z" fill="#ffffb0"/>
<path d="M60.8 64.3h27.9v12.7h-27.9z" fill="none" stroke="#800000" stroke-width=".21"/>
<path d="M63.3 56.6v7.7M65.8 56.6v7.7M68.4 56.6v7.7M70.9 56.6v7.7M73.4 56.6v7.7M76 56.6v7.7M78.5 56.6v7.7M81.1 56.6v7.7M83.6 56.6v7.7M86.2 56.6v7.7" fill="none" stroke="#000" stroke-width=".25"/>
<path d="M88.7 29.9h-7.6v7.7M93.8 35.1h-7.6v2.5M81.1 51.6v5M86.2 51.6v5" fill="none" stroke="#000080" stroke-width=".25"/>
<path d="M121.9 64.3h22.8v12.7h-22.8z" fill="#ffffb0"/>
<path d="M121.8 64.3h22.9v12.7h-22.9z" fill="none" stroke="#800000" stroke-width=".21"/>
<path d="M124.3 56.6v7.7M126.9 56.6v7.7M129.4 56.6v7.7M131.9 56.6v7.7M134.5 56.6v7.7M137.1 56.6v7.7M139.6 56.6v7.7M142.2 56.6v7.7" fill="none" stroke="#000" stroke-width=".25"/>
<path d="M111.6 27.4h20.3v10.2M142.2 27.4h-7.7v10.2M131.9 51.6v5M134.5 51.6v5" fill="none" stroke="#000080" stroke-width=".25"/>
<path d="M114.2 166.1h17.7v12.6h-17.7z" fill="#ffffb0"/>
<path d="M114.2 166h17.7v12.7h-17.7z" fill="none" stroke="#800000" stroke-width=".21"/>
<path d="M116.7 178.7v7.6M119.2 178.7v7.6M121.8 178.7v7.6M124.3 178.7v7.6M126.9 178.7v7.6M129.4 178.7v7.6" fill="none" stroke="#000" stroke-width=".25"/>
<path d="M73.5 166.1h22.8v12.6h-22.8z" fill="#ffffb0"/>
<path d="M73.5 166h22.8v12.7h-22.8z" fill="none" stroke="#800000" stroke-width=".21"/>
<path d="M76 178.7v7.6M78.5 178.7v7.6M81.1 178.7v7.6M83.6 178.7v7.6M86.2 178.7v7.6" fill="none" stroke="#000" stroke-width=".25"/>
<circle cx="86.1" cy="186.3" r=".73" fill="#000080"/>
<circle cx="86.1" cy="186.3" r=".73" fill="none" stroke="#000080" stroke-width=".21"/>
<path d="M88.7 178.7v7.6M91.3 178.7v7.6" fill="none" stroke="#000" stroke-width=".25"/>
<circle cx="91.2" cy="186.3" r=".5" fill="#000080"/>
<circle cx="91.2" cy="186.3" r=".5" fill="none" stroke="#000080" stroke-width=".21"/>
<path d="M93.8 178.7v7.6" fill="none" stroke="#000" stroke-width=".25"/>
<circle cx="86.1" cy="186.3" r=".73" fill="#000080"/>
<circle cx="86.1" cy="186.3" r=".73" fill="none" stroke="#000080" stroke-width=".21"/>
<circle cx="91.2" cy="186.3" r=".5" fill="#000080"/>
<circle cx="91.2" cy="186.3" r=".5" fill="none" stroke="#000080" stroke-width=".21"/>
<path d="M88.7 188.8h5.1M89.5 189.6h3.5M90.3 190.4h2M91 191.1h.5M91.3 186.3v2.5" fill="none" stroke="#800000" stroke-width=".25"/>
<circle cx="91.2" cy="186.3" r=".5" fill="#000080"/>
<circle cx="91.2" cy="186.3" r=".5" fill="none" stroke="#000080" stroke-width=".21"/>
<path d="M88.7 186.3h2.6" fill="none" stroke="#000080" stroke-width=".25"/>
<circle cx="91.2" cy="186.3" r=".5" fill="#000080"/>
<circle cx="91.2" cy="186.3" r=".5" fill="none" stroke="#000080" stroke-width=".21"/>
<path d="M86.2 186.3v5.1h-33.1" fill="none" stroke="#f00" stroke-width=".76"/>
<circle cx="86.1" cy="186.3" r=".73" fill="#000080"/>
<circle cx="86.1" cy="186.3" r=".73" fill="none" stroke="#000080" stroke-width=".21"/>
<path d="M236.3 31.2v7.7M238.8 31.2v7.7M241.3 31.2v7.7M243.9 31.2v7.7M246.5 31.2v7.7M251.5 31.2v7.7" fill="none" stroke="#000080" stroke-width=".25"/>
<path d="M229.9 23.6h2.5M231.2 23.6v2.5" fill="none" stroke="#800000" stroke-width=".25"/>
<circle cx="231.1" cy="26.1" r=".49" fill="#000080"/>
<circle cx="231.1" cy="26.1" r=".49" fill="none" stroke="#000080" stroke-width=".21"/>
<path d="M247.7 18.5h2.6M249 18.5v2.5M222.3 51.6h5.1M223.1 52.3h3.5M223.8 53.1h2M224.6 53.8h.5M224.8 49v2.6" fill="none" stroke="#800000" stroke-width=".25"/>
<circle cx="248.9" cy="21" r=".48" fill="#000080"/>
<circle cx="248.9" cy="21" r=".48" fill="none" stroke="#000080" stroke-width=".21"/>
<path d="M246.5 21h5M251.5 33.8h5.1v3.8h3.8" fill="none" stroke="#000080" stroke-width=".25"/>
<path d="M260.4 37.6h2.1M262.5 35.3v4.6M263.5 37.6h2M263.5 35.3v4.6" fill="none" stroke="#000" stroke-width=".25"/>
<circle cx="256.6" cy="33.7" r=".48" fill="#000080"/>
<circle cx="256.6" cy="33.7" r=".48" fill="none" stroke="#000080" stroke-width=".21"/>
<circle cx="251.5" cy="33.7" r=".49" fill="#000080"/>
<circle cx="251.5" cy="33.7" r=".49" fill="none" stroke="#000080" stroke-width=".21"/>
<path d="M271.9 36.3h5.1M272.7 37.1h3.5M273.4 37.8h2.1M274.2 38.6h.5M274.4 33.8v2.5" fill="none" stroke="#800000" stroke-width=".25"/>
<path d="M274.4 33.8h-5.1v3.8h-3.8" fill="none" stroke="#000080" stroke-width=".25"/>
<circle cx="269.3" cy="33.7" r=".48" fill="#000080"/>
<circle cx="269.3" cy="33.7" r=".48" fill="none" stroke="#000080" stroke-width=".21"/>
<path d="M48 35.1h17.8v2.5M48 37.6h15.3M63.3 51.6v5M65.8 51.6v5M236.3 82.1v10.1M243.9 82.1v12.7h17.8M246.5 82.1v10.1h15.2" fill="none" stroke="#000080" stroke-width=".25"/>
<path d="M257.9 97.3h2.5M259.2 97.3v2.6M233.7 104.9h5.1M234.5 105.7h3.5M235.2 106.5h2.1M236 107.2h.5M236.3 102.4v2.5" fill="none" stroke="#800000" stroke-width=".25"/>
<circle cx="259.1" cy="99.8" r=".49" fill="#000080"/>
<circle cx="259.1" cy="99.8" r=".49" fill="none" stroke="#000080" stroke-width=".21"/>
<path d="M241.3 82.1v30.5h17.9" fill="none" stroke="#000080" stroke-width=".25"/>
<circle cx="259.1" cy="112.5" r=".49" fill="#000080"/>
<circle cx="259.1" cy="112.5" r=".49" fill="none" stroke="#000080" stroke-width=".21"/>
<path d="M238.8 82.1v27.9h1.8a.74 .74 0 0 1 .7-.7 .74 .74 0 0 1 .8 .7M256.6 99.9h2.6M242.1 110h14.5" fill="none" stroke="#000080" stroke-width=".25"/>
<circle cx="259.1" cy="99.8" r=".49" fill="#000080"/>
<circle cx="259.1" cy="99.8" r=".49" fill="none" stroke="#000080" stroke-width=".21"/>
<path d="M259.2 112.6h5" fill="none" stroke="#000080" stroke-width=".25"/>
<circle cx="259.1" cy="112.5" r=".49" fill="#000080"/>
<circle cx="259.1" cy="112.5" r=".49" fill="none" stroke="#000080" stroke-width=".21"/>
<path d="M259.2 110v2.6" fill="none" stroke="#000080" stroke-width=".25"/>
<circle cx="259.1" cy="112.5" r=".49" fill="#000080"/>
<circle cx="259.1" cy="112.5" r=".49" fill="none" stroke="#000080" stroke-width=".21"/>
<path d="M259.2 112.6v7.6" fill="none" stroke="#000080" stroke-width=".25"/>
<circle cx="259.1" cy="112.5" r=".49" fill="#000080"/>
<circle cx="259.1" cy="112.5" r=".49" fill="none" stroke="#000080" stroke-width=".21"/>
<path d="M238.8 120.2h10.2" fill="none" stroke="#000080" stroke-width=".25"/>
<path d="M274.4 115.1h5.1M275.2 115.9h3.6M276 116.7h2M276.7 117.4h.5M277 112.6v2.5" fill="none" stroke="#800000" stroke-width=".25"/>
<g fill="none" stroke="#000" stroke-width=".25">
<path d="M32.8 99.9v2M32.8 104.9a1 1 0 0 0-1.1 1 1 1 0 0 0 1.1 1M32.8 102.9a1 1 0 0 1 .9 1 1 1 0 0 1-.9 1M32.8 108v2"/>
<circle cx="32.7" cy="107.5" r=".48"/>
<circle cx="32.7" cy="102.4" r=".48"/>
</g>
<path d="M32.8 87.2h7.6M32.8 110v12.8" fill="none" stroke="#000080" stroke-width=".76"/>
<circle cx="32.7" cy="87.1" r=".73" fill="#000080"/>
<circle cx="32.7" cy="87.1" r=".73" fill="none" stroke="#000080" stroke-width=".21"/>
<path d="M32.8 87.2v12.7" fill="none" stroke="#000080" stroke-width=".76"/>
<circle cx="32.7" cy="87.1" r=".73" fill="#000080"/>
<circle cx="32.7" cy="87.1" r=".73" fill="none" stroke="#000080" stroke-width=".21"/>
<path d="M45.5 84.7h22.9v12.6h-22.9z" fill="#ffffb0"/>
<path d="M45.5 84.7h22.9v12.6h-22.9z" fill="none" stroke="#800000" stroke-width=".21"/>
<path d="M40.4 87.2h5.1M55.7 97.3v5.1" fill="none" stroke="#000" stroke-width=".25"/>
<circle cx="55.6" cy="102.4" r=".49" fill="#000080"/>
<circle cx="55.6" cy="102.4" r=".49" fill="none" stroke="#000080" stroke-width=".21"/>
<path d="M68.4 87.2h5" fill="none" stroke="#000" stroke-width=".25"/>
<circle cx="73.4" cy="87.1" r=".74" fill="#000080"/>
<circle cx="73.4" cy="87.1" r=".74" fill="none" stroke="#000080" stroke-width=".21"/>
<path d="M68.4 89.7h5" fill="none" stroke="#000" stroke-width=".25"/>
<circle cx="55.6" cy="102.4" r=".49" fill="#000080"/>
<circle cx="55.6" cy="102.4" r=".49" fill="none" stroke="#000080" stroke-width=".21"/>
<circle cx="73.4" cy="87.1" r=".74" fill="#000080"/>
<circle cx="73.4" cy="87.1" r=".74" fill="none" stroke="#000080" stroke-width=".21"/>
<path d="M73.4 87.2h25.5" fill="none" stroke="#000080" stroke-width=".76"/>
<circle cx="73.4" cy="87.1" r=".74" fill="#000080"/>
<circle cx="73.4" cy="87.1" r=".74" fill="none" stroke="#000080" stroke-width=".21"/>
<circle cx="98.9" cy="87.1" r=".74" fill="#000080"/>
<circle cx="98.9" cy="87.1" r=".74" fill="none" stroke="#000080" stroke-width=".21"/>
<path d="M98.9 87.2v27.9" fill="none" stroke="#000080" stroke-width=".76"/>
<circle cx="98.9" cy="87.1" r=".74" fill="#000080"/>
<circle cx="98.9" cy="87.1" r=".74" fill="none" stroke="#000080" stroke-width=".21"/>
<circle cx="98.9" cy="115.1" r=".74" fill="#000080"/>
<circle cx="98.9" cy="115.1" r=".74" fill="none" stroke="#000080" stroke-width=".21"/>
<path d="M91.3 115.1h7.6" fill="none" stroke="#000080" stroke-width=".76"/>
<circle cx="98.9" cy="115.1" r=".74" fill="#000080"/>
<circle cx="98.9" cy="115.1" r=".74" fill="none" stroke="#000080" stroke-width=".21"/>
<path d="M121.9 42.8h22.8v7.5h-22.8z" fill="#ffffb0"/>
<path d="M121.8 42.7h22.9v7.6h-22.9z" fill="none" stroke="#800000" stroke-width=".21"/>
<path d="M124.3 37.6v5.1M126.9 37.6v5.1M129.4 37.6v5.1M131.9 37.6v5.1M134.5 37.6v5.1M137.1 37.6v5.1M139.6 37.6v5.1M142.2 37.6v5.1" fill="none" stroke="#000" stroke-width=".25"/>
<path d="M111.6 29.9h17.8v7.7" fill="none" stroke="#000080" stroke-width=".25"/>
<path d="M73.5 155.9h22.8v7.5h-22.8z" fill="#ffffb0"/>
<path d="M73.5 155.8h22.8v7.6h-22.8z" fill="none" stroke="#800000" stroke-width=".21"/>
<path d="M86.2 150.7v5.1M88.7 150.7v5.1M91.3 150.7v5.1M93.8 150.7v5.1" fill="none" stroke="#000" stroke-width=".25"/>
<circle cx="86.1" cy="150.7" r=".49" fill="#000080"/>
<circle cx="86.1" cy="150.7" r=".49" fill="none" stroke="#000080" stroke-width=".21"/>
<path d="M76 150.7v5.1M78.5 150.7v5.1M81.1 150.7v5.1M83.6 150.7v5.1" fill="none" stroke="#000" stroke-width=".25"/>
<circle cx="86.1" cy="150.7" r=".49" fill="#000080"/>
<circle cx="86.1" cy="150.7" r=".49" fill="none" stroke="#000080" stroke-width=".21"/>
<path d="M86.2 150.7v35.6" fill="none" stroke="#f00" stroke-width=".25"/>
<circle cx="86.1" cy="186.3" r=".73" fill="#000080"/>
<circle cx="86.1" cy="186.3" r=".73" fill="none" stroke="#000080" stroke-width=".21"/>
<circle cx="86.1" cy="150.7" r=".49" fill="#000080"/>
<circle cx="86.1" cy="150.7" r=".49" fill="none" stroke="#000080" stroke-width=".21"/>
<path d="M60.8 42.8h27.9v7.5h-27.9z" fill="#ffffb0"/>
<path d="M60.8 42.7h27.9v7.6h-27.9z" fill="none" stroke="#800000" stroke-width=".21"/>
<path d="M68.4 37.6v5.1M70.9 37.6v5.1" fill="none" stroke="#000" stroke-width=".25"/>
<circle cx="70.9" cy="37.5" r=".48" fill="#000080"/>
<circle cx="70.9" cy="37.5" r=".48" fill="none" stroke="#000080" stroke-width=".21"/>
<path d="M63.3 37.6v5.1M65.8 37.6v5.1M73.4 37.6v5.1M76 37.6v5.1M78.5 37.6v5.1M81.1 37.6v5.1M83.6 37.6v5.1M86.2 37.6v5.1" fill="none" stroke="#000" stroke-width=".25"/>
<circle cx="70.9" cy="37.5" r=".48" fill="#000080"/>
<circle cx="70.9" cy="37.5" r=".48" fill="none" stroke="#000080" stroke-width=".21"/>
<path d="M63.3 27.4h7.6v29.2" fill="none" stroke="#000080" stroke-width=".25"/>
<path d="M114.2 155.9h17.7v7.5h-17.7z" fill="#ffffb0"/>
<path d="M114.2 155.8h17.7v7.6h-17.7z" fill="none" stroke="#800000" stroke-width=".21"/>
<path d="M208.3 38.9v2.5M203.2 43.9h2.5M208.3 46.5v2.5M116.7 150.7v5.1M119.2 150.7v5.1M121.8 150.7v5.1M124.3 150.7v5.1M126.9 150.7v5.1M129.4 150.7v5.1" fill="none" stroke="#000" stroke-width=".25"/>
<path d="M91.3 32.5h-7.7v5.1M83.6 51.6v5M124.3 51.6v5M126.9 51.6v5M129.4 51.6v5" fill="none" stroke="#000080" stroke-width=".25"/>
<circle cx="208.3" cy="38.8" r=".48" fill="#000080"/>
<circle cx="208.3" cy="38.8" r=".48" fill="none" stroke="#000080" stroke-width=".21"/>
<path d="M205.7 41.4v5.1M205.7 45.2l2.6 1.3M207 45.2l.8 1h-1.3zM208.3 41.4l-2.6 1.3" fill="none" stroke="#000" stroke-width=".25"/>
<path d="M207 45.2l.8 1h-1.3z" fill="#000"/>
<circle cx="208.3" cy="38.8" r=".48" fill="#000080"/>
<circle cx="208.3" cy="38.8" r=".48" fill="none" stroke="#000080" stroke-width=".21"/>
<path d="M210.8 26.1h5.1v2.6M213.4 28.7h1.2M214.1 26.1v2.6M215.4 23.6l1.3-.8v1.5zM215.4 23.6h-2v2.5M215.4 28.7h1M215.6 22.8l-.2 .3v1l-.3 .2M215.9 26.1l.5 1.5h-1zM216.7 23.6h1.8v2.5M217.2 28.7h1.3M218.5 29.2h-5.1v2M221 26.1h-3.3v2.6" fill="none" stroke="#000" stroke-width=".25"/>
<path d="M215.4 23.6l1.3-.8v1.5zM215.9 26.1l.5 1.5h-1z" fill="#000"/>
<path d="M231.2 38.9h2.5" fill="none" stroke="#000080" stroke-width=".25"/>
<circle cx="231.2" cy="38.8" r=".48" fill="#000080"/>
<circle cx="231.2" cy="38.8" r=".48" fill="none" stroke="#000080" stroke-width=".21"/>
<path d="M208.3 36.3v2.6" fill="none" stroke="#000" stroke-width=".25"/>
<circle cx="208.3" cy="38.8" r=".48" fill="#000080"/>
<circle cx="208.3" cy="38.8" r=".48" fill="none" stroke="#000080" stroke-width=".21"/>
<path d="M207.3 31.2h1.9v5h-1.9zM208.3 28.7v2.5" fill="none" stroke="#000" stroke-width=".25"/>
<circle cx="208.3" cy="38.8" r=".48" fill="#000080"/>
<circle cx="208.3" cy="38.8" r=".48" fill="none" stroke="#000080" stroke-width=".21"/>
<path d="M213.4 31.2v7.7h-5.1" fill="none" stroke="#000080" stroke-width=".25"/>
<circle cx="208.3" cy="38.8" r=".48" fill="#000080"/>
<circle cx="208.3" cy="38.8" r=".48" fill="none" stroke="#000080" stroke-width=".21"/>
<path d="M201.9 23.6h2.6M203.2 23.6v2.5" fill="none" stroke="#800000" stroke-width=".25"/>
<path d="M210.8 26.1h-2.5v2.6" fill="none" stroke="#000080" stroke-width=".25"/>
<circle cx="208.3" cy="26.1" r=".49" fill="#000080"/>
<circle cx="208.3" cy="26.1" r=".49" fill="none" stroke="#000080" stroke-width=".21"/>
<path d="M203.2 26.1h5.1" fill="none" stroke="#000080" stroke-width=".25"/>
<circle cx="208.3" cy="26.1" r=".49" fill="#000080"/>
<circle cx="208.3" cy="26.1" r=".49" fill="none" stroke="#000080" stroke-width=".21"/>
<path d="M193 43.9h2.6M195.6 42.9h5v2h-5zM200.7 43.9h2.5" fill="none" stroke="#000" stroke-width=".25"/>
<path d="M180.3 43.9h12.7" fill="none" stroke="#000080" stroke-width=".25"/>
<path d="M205.7 56.6h5.1M206.5 57.4h3.6M207.3 58.2h2M208 58.9h.5M208.3 54.1v2.5" fill="none" stroke="#800000" stroke-width=".25"/>
<circle cx="208.3" cy="54.1" r=".49" fill="#000080"/>
<circle cx="208.3" cy="54.1" r=".49" fill="none" stroke="#000080" stroke-width=".21"/>
<g fill="none" stroke="#000080" stroke-width=".25">
<path d="M106.5 35.1h17.8v2.5M106.5 32.5h20.4v5.1M165.1 59.2v10.1M167.6 59.2v10.1M170.1 59.2v10.1M172.7 59.2v10.1M175.2 59.2v10.1M177.8 59.2v10.1M180.3 59.2v10.1M182.8 59.2v10.1M185.4 59.2v10.1M146 87.2h10.1"/>
<path d="M165.1 89.7v7.6M167.6 89.7v7.6M170.1 89.7v7.6M172.7 89.7v7.6M175.2 89.7v7.6M177.8 89.7v7.6M180.3 89.7v7.6M182.8 89.7v7.6M185.4 89.7v7.6M187.9 89.7v7.6M165.1 117.7v5.1M167.6 117.7v5.1"/>
<path d="M170.1 117.7v10.1M172.7 117.7v10.1M175.2 117.7v10.1M177.8 117.7v5.1M180.3 117.7v5.1M182.8 117.7v5.1M185.4 117.7v5.1"/>
</g>
<path d="M26.4 19.8h2.6M34 19.8h2.6M104 97.3v3.8M101.7 101.1h4.6l-2.3 2.6zM101.7 103.7h4.6M104 103.7v3.8M107 103.9l1 1M107 101.9l1 1M108.5 104.7v.8h-.7zM108.5 102.7v.7h-.7z" fill="none" stroke="#000" stroke-width=".25"/>
<path d="M108.5 104.7v.8h-.7zM108.5 102.7v.7h-.7z" fill="#000"/>
<path d="M186.6 66.8h2.6M187.9 66.8v2.5" fill="none" stroke="#800000" stroke-width=".25"/>
<path d="M29 18.8h5v1.9h-5z" fill-rule="evenodd" fill="#fff"/>
<path d="M29 18.8h5v1.9h-5zM26.4 22.3h2.6M34 22.3h2.6" fill="none" stroke="#000" stroke-width=".25"/>
<path d="M29 21.3h5v2h-5z" fill-rule="evenodd" fill="#fff"/>
<path d="M26.4 27.4h2.6M29 21.3h5v2h-5zM34 27.4h2.6" fill="none" stroke="#000" stroke-width=".25"/>
<path d="M29 26.4h5v2h-5z" fill-rule="evenodd" fill="#fff"/>
<path d="M26.4 24.8h2.6M29 26.4h5v2h-5zM34 24.8h2.6" fill="none" stroke="#000" stroke-width=".25"/>
<path d="M29 23.8h5v2h-5z" fill-rule="evenodd" fill="#fff"/>
<path d="M29 23.8h5v2h-5zM53.1 117.7h2.6M60.7 117.7h2.6" fill="none" stroke="#000" stroke-width=".25"/>
<path d="M12.4 19.8h14M36.6 19.8h5.1M12.4 22.3h14M12.4 24.8h14M16.2 27.4h10.2M36.6 22.3h5.1M36.6 24.8h5.1M36.6 27.4h5.1" fill="none" stroke="#000080" stroke-width=".25"/>
<path d="M9.9 16h35.6v15.2h-35.6z" fill="none" stroke="#00f" stroke-width=".25"/>
<path d="M55.7 116.7h5v1.9h-5z" fill-rule="evenodd" fill="#fff"/>
<path d="M55.7 116.7h5v1.9h-5zM53.1 120.2h2.6M60.7 120.2h2.6" fill="none" stroke="#000" stroke-width=".25"/>
<path d="M55.7 119.2h5v2h-5z" fill-rule="evenodd" fill="#fff"/>
<path d="M55.7 119.2h5v2h-5z" fill="none" stroke="#000" stroke-width=".25"/>
<path d="M279.5 77h-12.7v7.6h2.5M249 82.1v7.6h20.3M251.5 82.1v5.1h17.8M40.4 117.7h12.7M40.4 120.2h12.7M58.9 125.3a.72 .72 0 0 0-.7-.8 .72 .72 0 0 0-.8 .8h-6.9v1.8a.74 .74 0 0 1 .8 .7 .74 .74 0 0 1-.8 .8v1.8h-5v-2.6h-2.6M59 125.3h4.3" fill="none" stroke="#000080" stroke-width=".25"/>
<path d="M162.6 74.5h27.9v10.1h-27.9z" fill="#ffffb0"/>
<path d="M162.5 74.5h28v10.1h-28z" fill="none" stroke="#800000" stroke-width=".21"/>
<g fill="none" stroke="#000" stroke-width=".25">
<path d="M165.1 69.3v5.2M167.6 69.3v5.2M170.1 69.3v5.2M172.7 69.3v5.2M175.2 69.3v5.2M177.8 69.3v5.2M180.3 69.3v5.2M182.8 69.3v5.2M185.4 69.3v5.2M187.9 69.3v5.2M165.1 84.6v5.1M167.6 84.6v5.1"/>
<path d="M170.1 84.6v5.1M172.7 84.6v5.1M175.2 84.6v5.1M177.8 84.6v5.1M180.3 84.6v5.1M182.8 84.6v5.1M185.4 84.6v5.1M187.9 84.6v5.1"/>
</g>
<path d="M162.6 102.5h27.9v10.1h-27.9z" fill="#ffffb0"/>
<path d="M162.5 102.4h28v10.2h-28z" fill="none" stroke="#800000" stroke-width=".21"/>
<g fill="none" stroke="#000" stroke-width=".25">
<path d="M165.1 97.3v5.1M167.6 97.3v5.1M170.1 97.3v5.1M172.7 97.3v5.1M175.2 97.3v5.1M177.8 97.3v5.1M180.3 97.3v5.1M182.8 97.3v5.1M185.4 97.3v5.1M187.9 97.3v5.1M165.1 112.6v5.1M167.6 112.6v5.1"/>
<path d="M170.1 112.6v5.1M172.7 112.6v5.1M175.2 112.6v5.1M177.8 112.6v5.1M180.3 112.6v5.1M182.8 112.6v5.1M185.4 112.6v5.1M187.9 112.6v5.1"/>
</g>
<path d="M137.1 37.6v-5.1h15.2v19.1h-1.8M139.6 37.6v-2.5h10.2v19h-1.8M142.2 37.6h5v19h-5M148 54.1a.74 .74 0 0 0-.8-.8 .74 .74 0 0 0-.7 .8h-6.9v2.5M148 51.6a.74 .74 0 0 0-.8-.8 .74 .74 0 0 0-.7 .8h-9.4v5M148 51.6h1a.74 .74 0 0 1 .8-.8 .74 .74 0 0 1 .7 .8" fill="none" stroke="#000080" stroke-width=".25"/>
<path d="M274.5 82.2h7.6v10h-7.6z" fill="#ffffb0"/>
<path d="M274.4 82.1h7.7v10.1h-7.7z" fill="none" stroke="#800000" stroke-width=".21"/>
<path d="M190.5 43.9v2.6M269.3 84.6h5.1M269.3 87.2h5.1M269.3 89.7h5.1" fill="none" stroke="#000" stroke-width=".25"/>
<circle cx="190.4" cy="43.9" r=".48" fill="#000080"/>
<circle cx="190.4" cy="43.9" r=".48" fill="none" stroke="#000080" stroke-width=".21"/>
<path d="M189.4 46.5h2v5h-2zM190.5 51.6v2.5" fill="none" stroke="#000" stroke-width=".25"/>
<circle cx="190.4" cy="43.9" r=".48" fill="#000080"/>
<circle cx="190.4" cy="43.9" r=".48" fill="none" stroke="#000080" stroke-width=".21"/>
<path d="M208.3 49v5.1h-17.8" fill="none" stroke="#000080" stroke-width=".25"/>
<circle cx="208.3" cy="54.1" r=".49" fill="#000080"/>
<circle cx="208.3" cy="54.1" r=".49" fill="none" stroke="#000080" stroke-width=".21"/>
<path d="M221 26.1h10.2v12.8h-6.4" fill="none" stroke="#000080" stroke-width=".25"/>
<circle cx="231.2" cy="38.8" r=".48" fill="#000080"/>
<circle cx="231.2" cy="38.8" r=".48" fill="none" stroke="#000080" stroke-width=".21"/>
<circle cx="231.1" cy="26.1" r=".49" fill="#000080"/>
<circle cx="231.1" cy="26.1" r=".49" fill="none" stroke="#000080" stroke-width=".21"/>
<path d="M226.1 84.6h5.1M226.9 85.4h3.5M227.6 86.1h2.1M228.4 86.9h.5M228.6 82.1v2.5" fill="none" stroke="#800000" stroke-width=".25"/>
<path d="M228.6 82.1h5.1" fill="none" stroke="#000080" stroke-width=".25"/>
<use href="#words"/>
</svg>
